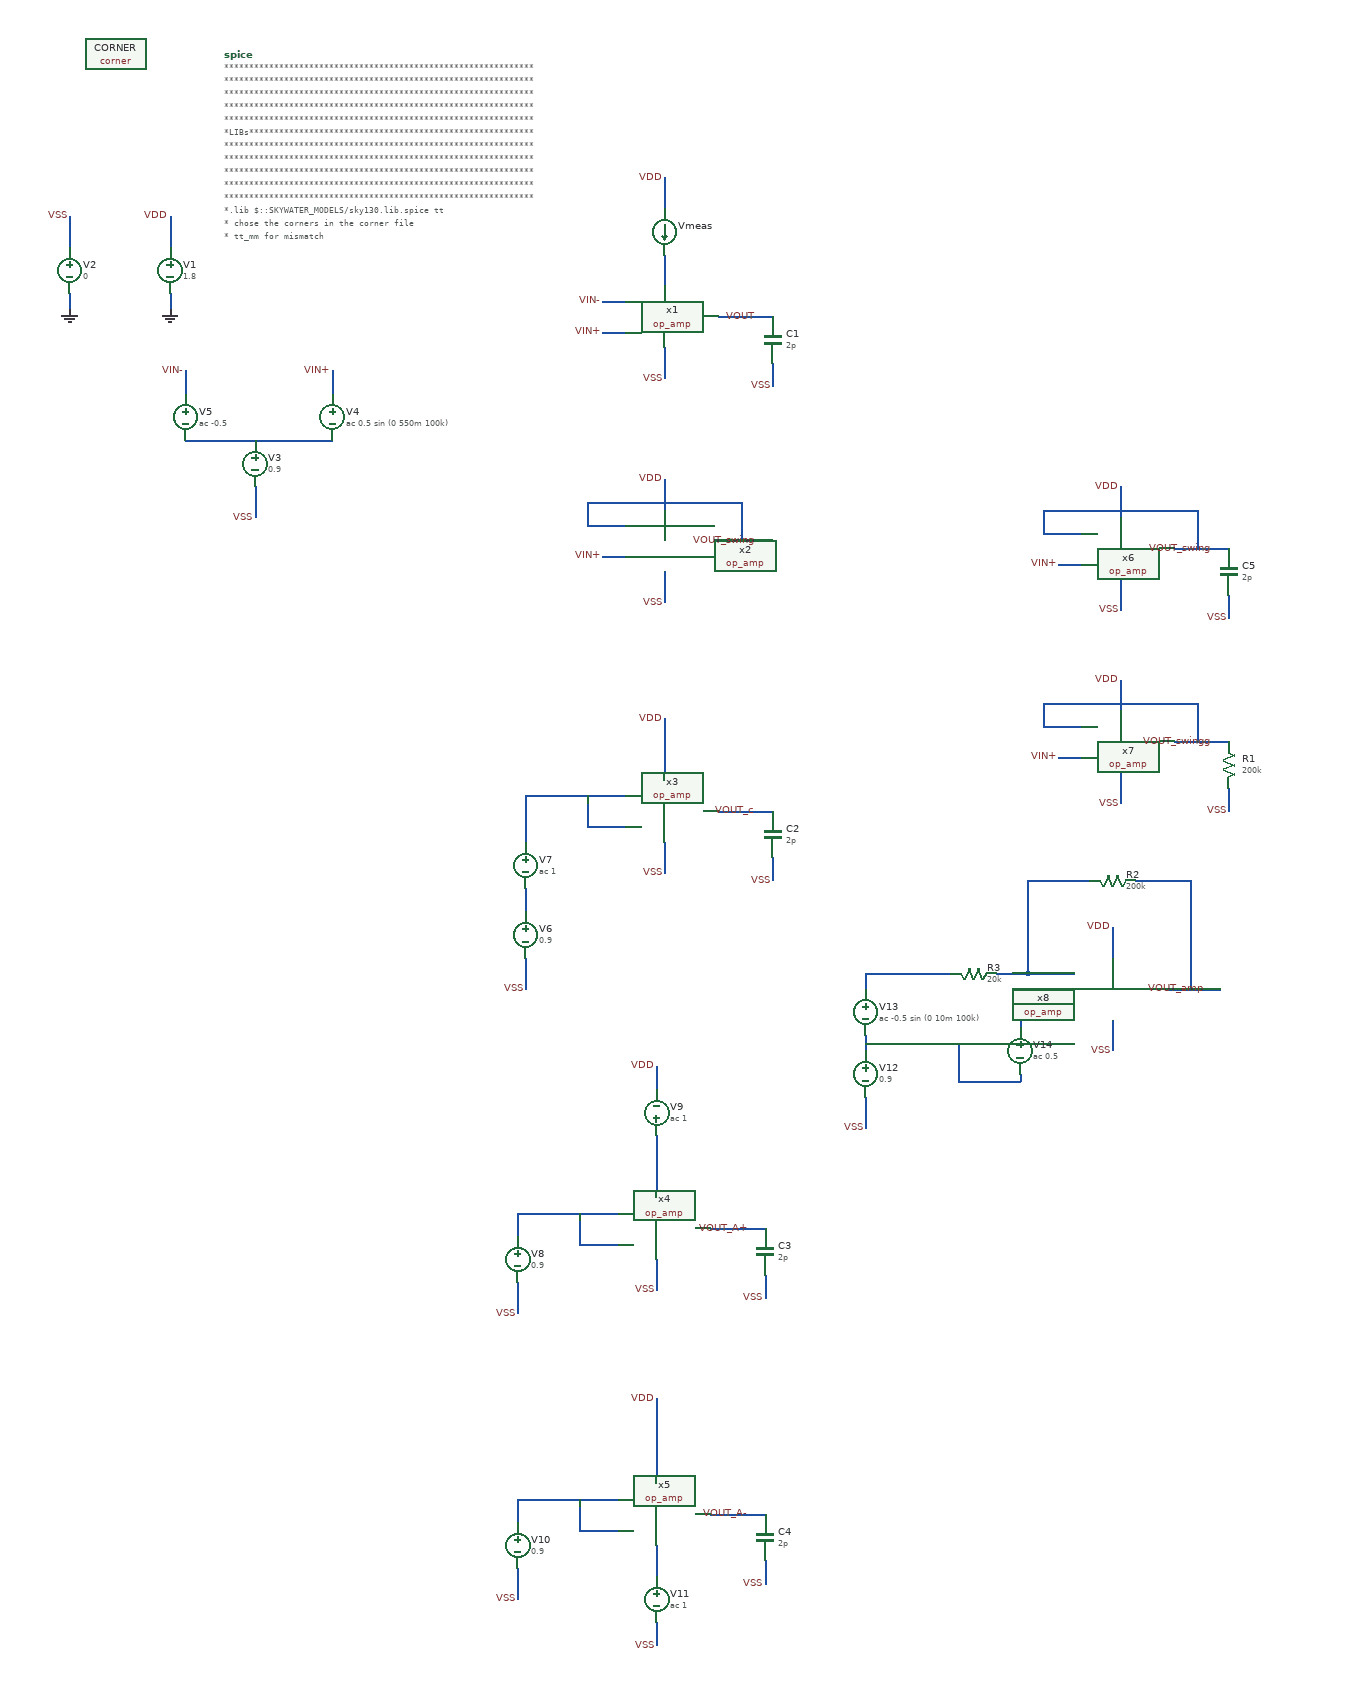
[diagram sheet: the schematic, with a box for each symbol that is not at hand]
v {xschem version=3.4.5 file_version=1.2
}
G {}
K {}
V {}
S {}
E {}
N -240 210 -240 230 {
lab=GND}
N -240 110 -240 150 {
lab=VDD}
N -370 210 -370 230 {
lab=GND}
N -370 110 -370 150 {
lab=VSS}
N -130 460 -130 480 {
lab=VSS}
N -130 480 -130 500 {
lab=VSS}
N -30 310 -30 340 {
lab=VIN+}
N -220 400 -30 400 {
lab=#net1}
N -220 310 -220 340 {
lab=VIN-}
N 400 160 400 200 {
lab=#net2}
N 400 280 400 320 {
lab=VSS}
N 320 260 350 260 {
lab=VIN+}
N 320 220 350 220 {
lab=VIN-}
N 470 240 540 240 {
lab=VOUT}
N 540 300 540 330 {
lab=VSS}
N 400 60 400 100 {
lab=VDD}
N 400 570 400 610 {
lab=VSS}
N 320 550 350 550 {
lab=VIN+}
N 470 530 540 530 {
lab=VOUT_swing}
N 400 450 400 490 {
lab=VDD}
N 500 480 500 530 {
lab=VOUT_swing}
N 300 480 500 480 {
lab=VOUT_swing}
N 300 480 300 510 {
lab=VOUT_swing}
N 300 510 350 510 {
lab=VOUT_swing}
N 400 800 400 840 {
lab=VDD}
N 400 920 400 960 {
lab=VSS}
N 320 900 350 900 {
lab=#net3}
N 320 860 350 860 {
lab=#net3}
N 470 880 540 880 {
lab=VOUT_c}
N 540 940 540 970 {
lab=VSS}
N 400 760 400 800 {
lab=VDD}
N 220 1070 220 1090 {
lab=VSS}
N 220 1090 220 1110 {
lab=VSS}
N 220 860 220 890 {
lab=#net3}
N 220 860 320 860 {
lab=#net3}
N 300 860 300 900 {
lab=#net3}
N 300 900 320 900 {
lab=#net3}
N 220 980 220 1010 {
lab=#net4}
N 220 890 220 920 {
lab=#net3}
N 390 1340 390 1380 {
lab=#net5}
N 390 1460 390 1500 {
lab=VSS}
N 310 1440 340 1440 {
lab=#net6}
N 310 1400 340 1400 {
lab=#net6}
N 460 1420 530 1420 {
lab=VOUT_A+}
N 530 1480 530 1510 {
lab=VSS}
N 390 1300 390 1340 {
lab=#net5}
N 210 1490 210 1510 {
lab=VSS}
N 210 1510 210 1530 {
lab=VSS}
N 290 1400 290 1440 {
lab=#net6}
N 290 1440 310 1440 {
lab=#net6}
N 210 1400 210 1430 {
lab=#net6}
N 210 1400 310 1400 {
lab=#net6}
N 390 1210 390 1240 {
lab=VDD}
N 390 1710 390 1750 {
lab=VDD}
N 390 1830 390 1870 {
lab=#net7}
N 310 1810 340 1810 {
lab=#net8}
N 310 1770 340 1770 {
lab=#net8}
N 460 1790 530 1790 {
lab=VOUT_A-}
N 530 1850 530 1880 {
lab=VSS}
N 390 1670 390 1710 {
lab=VDD}
N 210 1860 210 1880 {
lab=VSS}
N 210 1880 210 1900 {
lab=VSS}
N 290 1770 290 1810 {
lab=#net8}
N 290 1810 310 1810 {
lab=#net8}
N 210 1770 210 1800 {
lab=#net8}
N 210 1770 310 1770 {
lab=#net8}
N 390 1640 390 1670 {
lab=VDD}
N 390 1930 390 1960 {
lab=VSS}
N 990 580 990 620 {
lab=VSS}
N 910 560 940 560 {
lab=VIN+}
N 1060 540 1130 540 {
lab=VOUT_swing}
N 990 460 990 500 {
lab=VDD}
N 1090 490 1090 540 {
lab=VOUT_swing}
N 890 490 1090 490 {
lab=VOUT_swing}
N 890 490 890 520 {
lab=VOUT_swing}
N 890 520 940 520 {
lab=VOUT_swing}
N 1130 600 1130 630 {
lab=VSS}
N 990 830 990 870 {
lab=VSS}
N 910 810 940 810 {
lab=VIN+}
N 1060 790 1130 790 {
lab=VOUT_swingg}
N 990 710 990 750 {
lab=VDD}
N 1090 740 1090 790 {
lab=VOUT_swingg}
N 890 740 1090 740 {
lab=VOUT_swingg}
N 890 740 890 770 {
lab=VOUT_swingg}
N 890 770 940 770 {
lab=VOUT_swingg}
N 1130 850 1130 880 {
lab=VSS}
N 980 1150 980 1190 {
lab=VSS}
N 900 1130 930 1130 {
lab=#net9}
N 1050 1110 1120 1110 {
lab=VOUT_amp}
N 980 1030 980 1070 {
lab=VDD}
N 1080 1060 1080 1110 {
lab=VOUT_amp}
N 880 1090 930 1090 {
lab=#net10}
N 1080 970 1080 1060 {
lab=VOUT_amp}
N 1010 970 1080 970 {
lab=VOUT_amp}
N 870 970 950 970 {
lab=#net10}
N 870 970 870 1090 {
lab=#net10}
N 870 1090 880 1090 {
lab=#net10}
N 830 1090 870 1090 {
lab=#net10}
N 660 1250 660 1270 {
lab=VSS}
N 660 1270 660 1290 {
lab=VSS}
N 660 1170 660 1190 {
lab=#net11}
N 660 1090 660 1110 {
lab=#net12}
N 660 1090 770 1090 {
lab=#net12}
N 660 1180 780 1180 {
lab=#net11}
N 780 1180 780 1230 {
lab=#net11}
N 780 1230 860 1230 {
lab=#net11}
N 860 1220 860 1230 {
lab=#net11}
N 860 1130 860 1160 {
lab=#net9}
N 860 1130 900 1130 {
lab=#net9}
C {sky130_fd_pr/corner.sym} -310 -100 0 0 {name=CORNER only_toplevel=true corner=tt}
C {devices/code.sym} -170 -100 0 0 {name=spice only_toplevel=false
format="tcleval( @value )"
value="	
**************************************************************
**************************************************************
**************************************************************
**************************************************************
**************************************************************
*LIBs*********************************************************
**************************************************************
**************************************************************
**************************************************************
**************************************************************
**************************************************************
*.lib $::SKYWATER_MODELS/sky130.lib.spice tt
* chose the corners in the corner file
* tt_mm for mismatch
* ss ff sf fs standart corners
* ll hh lh hl capacitor and resistors corners
* mc for total process variation including corners
**************************************************************
**************************************************************
**************************************************************
**************************************************************
**************************************************************
*Corners/montecarlo options***********************************
**************************************************************
**************************************************************
**************************************************************
**************************************************************
**************************************************************
.TEMP 27
**************************************************************
**************************************************************
**************************************************************
**************************************************************  
*SIMULATION and Plots*****************************************
**************************************************************
**************************************************************
**************************************************************
**************************************************************
.control
save all
dc V3 0 1.8 0.001 
*dc simulation
plot i(Vmeas) 
plot v(VOUT_1)
plot v(VOUT)
plot v(VOUT_swing) 
ac dec 10 1 50G
plot db(v(VOUT)) (180*ph(v(VOUT))/pi)
plot (db(v(VOUT))-db(v(VOUT_c)))
plot (db(v(VOUT))-db(v(VOUT_A+)))
plot (db(v(VOUT))-db(v(VOUT_A-)))
plot db(v(VOUT_amp))
tran 1ns 20u
plot v(VOUT_swing) v(VIN+) v(VOUT_swingg)
plot v(VOUT_amp)
.endc
"}
C {devices/lab_pin.sym} -240 110 0 0 {name=p6 sig_type=std_logic lab=VDD}
C {devices/vsource.sym} -240 180 0 0 {name=V1 value=1.8

}
C {devices/gnd.sym} -240 230 0 0 {name=l3 lab=GND}
C {devices/lab_pin.sym} -370 110 0 0 {name=p1 sig_type=std_logic lab=VSS
}
C {devices/vsource.sym} -370 180 0 0 {name=V2 value=0


}
C {devices/gnd.sym} -370 230 0 0 {name=l1 lab=GND}
C {devices/vsource.sym} -130 430 0 0 {name=V3 value=0.9}
C {devices/lab_pin.sym} -130 500 0 0 {name=p7 sig_type=std_logic lab=VSS}
C {devices/lab_pin.sym} -30 310 0 0 {name=p12 sig_type=std_logic lab=VIN+
}
C {devices/vsource.sym} -30 370 0 0 {name=V4 value="ac 0.5 sin (0 550m 100k)"}
C {devices/vsource.sym} -220 370 0 0 {name=V5 value="ac -0.5"}
C {devices/lab_pin.sym} -220 310 0 0 {name=p13 sig_type=std_logic lab=VIN-
}
C {/home/vasco/Desktop/OSAD/my_ip/sky130A/2_stage_op_amp_sky130/op_amp.sym} 400 240 0 0 {name=x1}
C {devices/lab_pin.sym} 400 60 0 0 {name=p2 sig_type=std_logic lab=VDD}
C {devices/lab_pin.sym} 400 320 0 0 {name=p3 sig_type=std_logic lab=VSS
}
C {devices/lab_pin.sym} 320 260 0 0 {name=p4 sig_type=std_logic lab=VIN+
}
C {devices/lab_pin.sym} 320 220 0 0 {name=p5 sig_type=std_logic lab=VIN-
}
C {devices/capa.sym} 540 270 0 0 {name=C1
m=1
value=2p
footprint=1206
device="ceramic capacitor"}
C {devices/lab_pin.sym} 540 330 0 0 {name=p8 sig_type=std_logic lab=VSS}
C {devices/lab_pin.sym} 520 240 1 0 {name=p9 sig_type=std_logic lab=VOUT}
C {devices/ammeter.sym} 400 130 0 0 {name=Vmeas}
C {/home/vasco/Desktop/OSAD/my_ip/sky130A/2_stage_op_amp_sky130/op_amp.sym} 400 530 0 0 {name=x2}
C {devices/lab_pin.sym} 400 610 0 0 {name=p10 sig_type=std_logic lab=VSS
}
C {devices/lab_pin.sym} 320 550 0 0 {name=p11 sig_type=std_logic lab=VIN+
}
C {devices/lab_pin.sym} 520 530 1 0 {name=p15 sig_type=std_logic lab=VOUT_swing}
C {devices/lab_pin.sym} 400 450 0 0 {name=p16 sig_type=std_logic lab=VDD}
C {/home/vasco/Desktop/OSAD/my_ip/sky130A/2_stage_op_amp_sky130/op_amp.sym} 400 880 0 0 {name=x3}
C {devices/lab_pin.sym} 400 760 0 0 {name=p14 sig_type=std_logic lab=VDD}
C {devices/lab_pin.sym} 400 960 0 0 {name=p17 sig_type=std_logic lab=VSS
}
C {devices/capa.sym} 540 910 0 0 {name=C2
m=1
value=2p
footprint=1206
device="ceramic capacitor"}
C {devices/lab_pin.sym} 540 970 0 0 {name=p20 sig_type=std_logic lab=VSS}
C {devices/lab_pin.sym} 520 880 1 0 {name=p21 sig_type=std_logic lab=VOUT_c}
C {devices/vsource.sym} 220 1040 0 0 {name=V6 value=0.9}
C {devices/lab_pin.sym} 220 1110 0 0 {name=p18 sig_type=std_logic lab=VSS}
C {devices/vsource.sym} 220 950 0 0 {name=V7 value="ac 1"}
C {/home/vasco/Desktop/OSAD/my_ip/sky130A/2_stage_op_amp_sky130/op_amp.sym} 390 1420 0 0 {name=x4}
C {devices/lab_pin.sym} 390 1210 0 0 {name=p19 sig_type=std_logic lab=VDD}
C {devices/lab_pin.sym} 390 1500 0 0 {name=p22 sig_type=std_logic lab=VSS
}
C {devices/capa.sym} 530 1450 0 0 {name=C3
m=1
value=2p
footprint=1206
device="ceramic capacitor"}
C {devices/lab_pin.sym} 530 1510 0 0 {name=p23 sig_type=std_logic lab=VSS}
C {devices/lab_pin.sym} 510 1420 1 0 {name=p24 sig_type=std_logic lab=VOUT_A+}
C {devices/vsource.sym} 210 1460 0 0 {name=V8 value=0.9}
C {devices/lab_pin.sym} 210 1530 0 0 {name=p25 sig_type=std_logic lab=VSS}
C {devices/vsource.sym} 390 1270 2 0 {name=V9 value="ac 1"}
C {/home/vasco/Desktop/OSAD/my_ip/sky130A/2_stage_op_amp_sky130/op_amp.sym} 390 1790 0 0 {name=x5}
C {devices/lab_pin.sym} 390 1640 0 0 {name=p26 sig_type=std_logic lab=VDD}
C {devices/lab_pin.sym} 390 1960 0 0 {name=p27 sig_type=std_logic lab=VSS
}
C {devices/capa.sym} 530 1820 0 0 {name=C4
m=1
value=2p
footprint=1206
device="ceramic capacitor"}
C {devices/lab_pin.sym} 530 1880 0 0 {name=p28 sig_type=std_logic lab=VSS}
C {devices/lab_pin.sym} 510 1790 1 0 {name=p29 sig_type=std_logic lab=VOUT_A-}
C {devices/vsource.sym} 210 1830 0 0 {name=V10 value=0.9}
C {devices/lab_pin.sym} 210 1900 0 0 {name=p30 sig_type=std_logic lab=VSS}
C {devices/vsource.sym} 390 1900 0 0 {name=V11 value="ac 1"}
C {/home/vasco/Desktop/OSAD/my_ip/sky130A/2_stage_op_amp_sky130/op_amp.sym} 990 540 0 0 {name=x6}
C {devices/lab_pin.sym} 990 620 0 0 {name=p31 sig_type=std_logic lab=VSS
}
C {devices/lab_pin.sym} 910 560 0 0 {name=p32 sig_type=std_logic lab=VIN+
}
C {devices/lab_pin.sym} 1110 540 1 0 {name=p33 sig_type=std_logic lab=VOUT_swing}
C {devices/lab_pin.sym} 990 460 0 0 {name=p34 sig_type=std_logic lab=VDD}
C {devices/capa.sym} 1130 570 0 0 {name=C5
m=1
value=2p
footprint=1206
device="ceramic capacitor"}
C {devices/lab_pin.sym} 1130 630 0 0 {name=p35 sig_type=std_logic lab=VSS}
C {/home/vasco/Desktop/OSAD/my_ip/sky130A/2_stage_op_amp_sky130/op_amp.sym} 990 790 0 0 {name=x7}
C {devices/lab_pin.sym} 990 870 0 0 {name=p36 sig_type=std_logic lab=VSS
}
C {devices/lab_pin.sym} 910 810 0 0 {name=p37 sig_type=std_logic lab=VIN+
}
C {devices/lab_pin.sym} 1110 790 1 0 {name=p38 sig_type=std_logic lab=VOUT_swingg}
C {devices/lab_pin.sym} 990 710 0 0 {name=p39 sig_type=std_logic lab=VDD}
C {devices/lab_pin.sym} 1130 880 0 0 {name=p40 sig_type=std_logic lab=VSS}
C {devices/res.sym} 1130 820 0 0 {name=R1
value=200k
footprint=1206
device=resistor
m=1}
C {/home/vasco/Desktop/OSAD/my_ip/sky130A/2_stage_op_amp_sky130/op_amp.sym} 980 1110 0 0 {name=x8}
C {devices/lab_pin.sym} 980 1190 0 0 {name=p41 sig_type=std_logic lab=VSS
}
C {devices/lab_pin.sym} 1100 1110 1 0 {name=p43 sig_type=std_logic lab=VOUT_amp}
C {devices/lab_pin.sym} 980 1030 0 0 {name=p44 sig_type=std_logic lab=VDD}
C {devices/res.sym} 980 970 1 0 {name=R2
value=200k
footprint=1206
device=resistor
m=1}
C {devices/res.sym} 800 1090 1 0 {name=R3
value=20k
footprint=1206
device=resistor
m=1}
C {devices/vsource.sym} 660 1220 0 0 {name=V12 value=0.9}
C {devices/lab_pin.sym} 660 1290 0 0 {name=p45 sig_type=std_logic lab=VSS}
C {devices/vsource.sym} 660 1140 0 0 {name=V13 value="ac -0.5 sin (0 10m 100k)"}
C {devices/vsource.sym} 860 1190 0 0 {name=V14 value="ac 0.5"}
